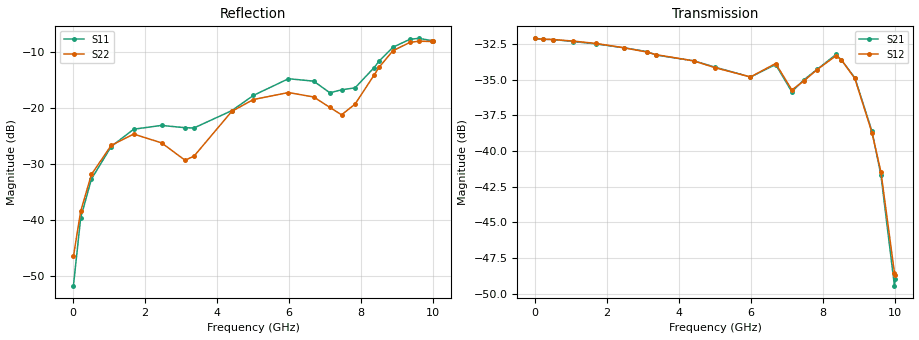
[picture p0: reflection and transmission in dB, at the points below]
! Device ID: PE43704
! Dir: z:\PE43704\PE43704_Char_1_20130516\PE43704\AMB\3p400V\31p25dB
! Serial: 14
! Insertion: A
! Impedance: 50 ohm
! Temp: Amb
! VDD: 3.400V
! Attenuation Step: 31.25dB
! IDD: 1.140341e-01mA
#  Hz  S  RI  R  50
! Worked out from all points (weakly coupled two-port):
!   401 points, 10 MHz to 10.01 GHz, reference 50 ohm
!   highest |S21| = -32.11 dB at 10 MHz (marker M1); lowest = -49.4 dB at 9.985 GHz (marker M2)
!   lowest |S11| = -51.7 dB at 10 MHz (marker M3), VSWR 1.01, Z = 50.3 + j0.0457 ohm
!   |S11| at or under -10 dB: start of sweep to 8.725 GHz
!   |S22| runs from -46.4 to -7.9 dB; largest |S21 - S12| = 0.0007
!   S11 on the Smith chart (normalised r, x): 10 MHz: 1.01, +0.00; 7.46 GHz: 0.79, +0.15; 8.51 GHz: 0.81, +0.46; 9.36 GHz: 0.54, +0.49; 10.01 GHz: 0.47, +0.28
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1e7  0.00257 0.000455  0.0248 -6.01e-05  0.0248 -6.78e-05  -0.00474 0.000462
2.1e8  0.00127 0.0104  0.0246 -0.0012  0.0246 -0.00119  -0.00547 0.0107
5.1e8  -0.00681 0.0224  0.0244 -0.00282  0.0244 -0.00284  -0.0128 0.0223
1.06e9  -0.0346 0.0298  0.0235 -0.00568  0.0236 -0.00564  -0.0369 0.0287
1.685e9  -0.0632 0.0161  0.0221 -0.00862  0.0222 -0.00861  -0.0573 0.0139
2.46e9  -0.0703 -0.00503  0.0198 -0.0117  0.0198 -0.0117  -0.0492 -0.000553
3.11e9  -0.067 -0.00524  0.0175 -0.0138  0.0174 -0.0138  -0.0333 0.00886
3.36e9  -0.0669 0.00072  0.0163 -0.0143  0.0163 -0.0144  -0.0333 0.0171
4.41e9  -0.0841 0.0453  0.013 -0.0161  0.0131 -0.016  -0.075 0.0569
5.01e9  -0.1076 0.074  0.0114 -0.016  0.0114 -0.0159  -0.1056 0.057
5.985e9  -0.1563 0.0973  0.0082 -0.0162  0.00823 -0.0162  -0.1316 0.0433
6.685e9  -0.154 0.0834  0.00731 -0.0187  0.00727 -0.0189  -0.1215 0.035
7.135e9  -0.1236 0.061  0.00364 -0.0157  0.00346 -0.016  -0.0914 0.0454
7.46e9  -0.1124 0.094  0.00428 -0.0172  0.00437 -0.017  -0.0656 0.0581
7.835e9  -0.0657 0.1378  0.00438 -0.0188  0.00423 -0.0188  -0.0522 0.096
8.36e9  -0.0329 0.2283  -0.00278 -0.0216  -0.00254 -0.0214  -0.0719 0.1843
8.51e9  -0.036 0.2635  -0.00511 -0.0202  -0.00486 -0.0203  -0.0869 0.218
8.885e9  -0.0809 0.3419  -0.00957 -0.0153  -0.00954 -0.0152  -0.1505 0.2904
9.36e9  -0.1784 0.3742  -0.00891 -0.00765  -0.00881 -0.00756  -0.2509 0.2972
9.61e9  -0.2385 0.3483  -0.00636 -0.00522  -0.00658 -0.00529  -0.3057 0.2549
9.985e9  -0.3082 0.2579  -0.00119 -0.00316  -0.000935 -0.00363  -0.3688 0.144
1.001e10  -0.3132 0.2497  -0.000191 -0.00357  -0.000458 -0.00364  -0.3727 0.1356
